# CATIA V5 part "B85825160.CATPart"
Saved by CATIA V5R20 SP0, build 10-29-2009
Part number: B85825160
Revision: 4
Definition: design
Nomenclature: B85825160
Source: made
Description: NOT SPECIFIED
Bounding box of the stored display mesh (mm): x -15 to 15, y -15 to 15, z 0 to 160
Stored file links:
  C:\Users\Raffaele\Desktop\3D X SITO CF\BOLEX\12-PILLAR REF 858\B85825160.CATPart

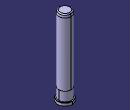
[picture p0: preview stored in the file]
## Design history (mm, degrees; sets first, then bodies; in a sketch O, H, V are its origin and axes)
Body1 "MANIFOLD_SOLID_BREP #450" (main body)
  Solid1: solid without history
